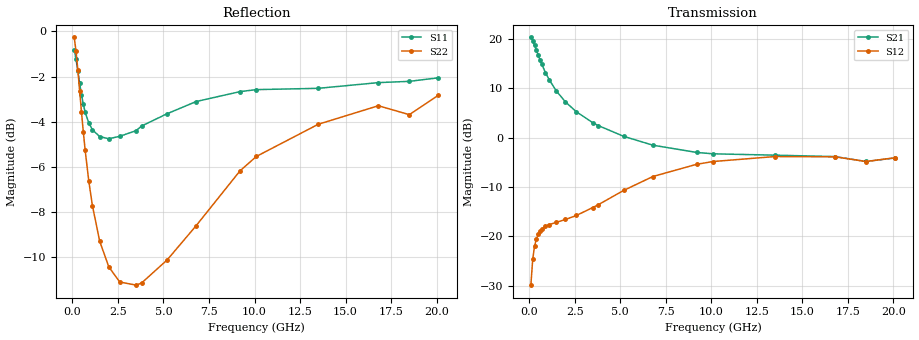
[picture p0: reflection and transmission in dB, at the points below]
!  Infineon Technologies AG
! BFR380L3 , PF131585-7, No.6, Th 09.10.01, soldered on pcb-board, measured with PP GSG850
!  Vce=2.0 V,  Ic=3.0 mA
! Common Emitter S-Parameters:  15. November 2001
#  GHz  S  MA  R  50
! f  S11  S21  S12  S22
! GHz  Mag  Ang  Mag  Ang  Mag  Ang  Mag  Ang
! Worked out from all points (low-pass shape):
!   201 points, 100 MHz to 20.1 GHz, reference 50 ohm
!   highest |S21| = 20.33 dB at 100 MHz (marker M1); lowest = -4.8 dB at 18.5 GHz (marker M2)
!   |S21| within 3 dB of the highest: start of sweep to 443.5 MHz
!   lowest |S11| = -4.7 dB at 2 GHz (marker M3), VSWR 3.75, Z = 13.4 - j1.72 ohm
!   |S11| at or under -10 dB: nowhere
!   |S22| runs from -11.3 to -0.3 dB; largest |S21 - S12| = 10
!   S11 on the Smith chart (normalised r, x): 100 MHz: 1.15, -4.76; 400 MHz: 0.33, -1.20; 1.1 GHz: 0.27, -0.34; 3.8 GHz: 0.26, +0.29; 9.2 GHz: 0.33, +1.07; 20.1 GHz: 0.97, +2.54
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0.1  0.9119 -22.5  10.38 165.0  0.03207 77.0  0.9701 -12.8
0.2  0.8675 -42.9  9.564 151.4  0.0584 66.8  0.9053 -24.3
0.3  0.8165 -61.4  8.652 139.8  0.0792 58.0  0.8213 -33.8
0.4  0.7677 -77.2  7.731 130.0  0.09396 51.0  0.7375 -41.3
0.5  0.7249 -90.8  6.887 121.9  0.1045 46.0  0.6632 -47.1
0.6  0.6901 -102.1  6.153 115.3  0.1124 42.2  0.5997 -51.8
0.7  0.6631 -112.0  5.538 109.5  0.1181 39.3  0.5468 -55.5
0.9  0.6277 -127.9  4.571 100.3  0.126 35.7  0.4669 -61.1
1.1  0.6061 -140.4  3.883 92.9  0.1314 33.8  0.4118 -65.4
1.5  0.5853 -159.1  2.969 81.1  0.1389 33.3  0.3435 -71.8
2  0.5789 -175.8  2.303 69.5  0.1483 35.3  0.3015 -79.3
2.6  0.5861 169.2  1.83 58.0  0.1629 39.3  0.2791 -89.1
3.5  0.6033 151.0  1.417 43.4  0.1961 44.8  0.2747 -104.9
3.8  0.6177 146.2  1.327 39.4  0.2092 45.8  0.2777 -111.6
5.2  0.6575 125.2  1.031 22.7  0.2925 45.6  0.3122 -139.2
6.8  0.6998 105.1  0.8392 9.6  0.4042 38.4  0.372 -171.7
9.2  0.7359 83.3  0.709 -2.1  0.5373 21.0  0.4914 150.3
10.1  0.7435 76.7  0.6863 -5.5  0.5732 14.4  0.529 138.1
13.5  0.7484 58.6  0.665 -19.1  0.6439 -9.0  0.6232 102.4
16.8  0.7705 47.1  0.6433 -30.9  0.6398 -25.8  0.6849 78.4
18.5  0.7755 45.2  0.5738 -38.9  0.5736 -34.4  0.6545 72.3
20.1  0.7896 38.5  0.6233 -42.7  0.6265 -39.5  0.7226 61.2
